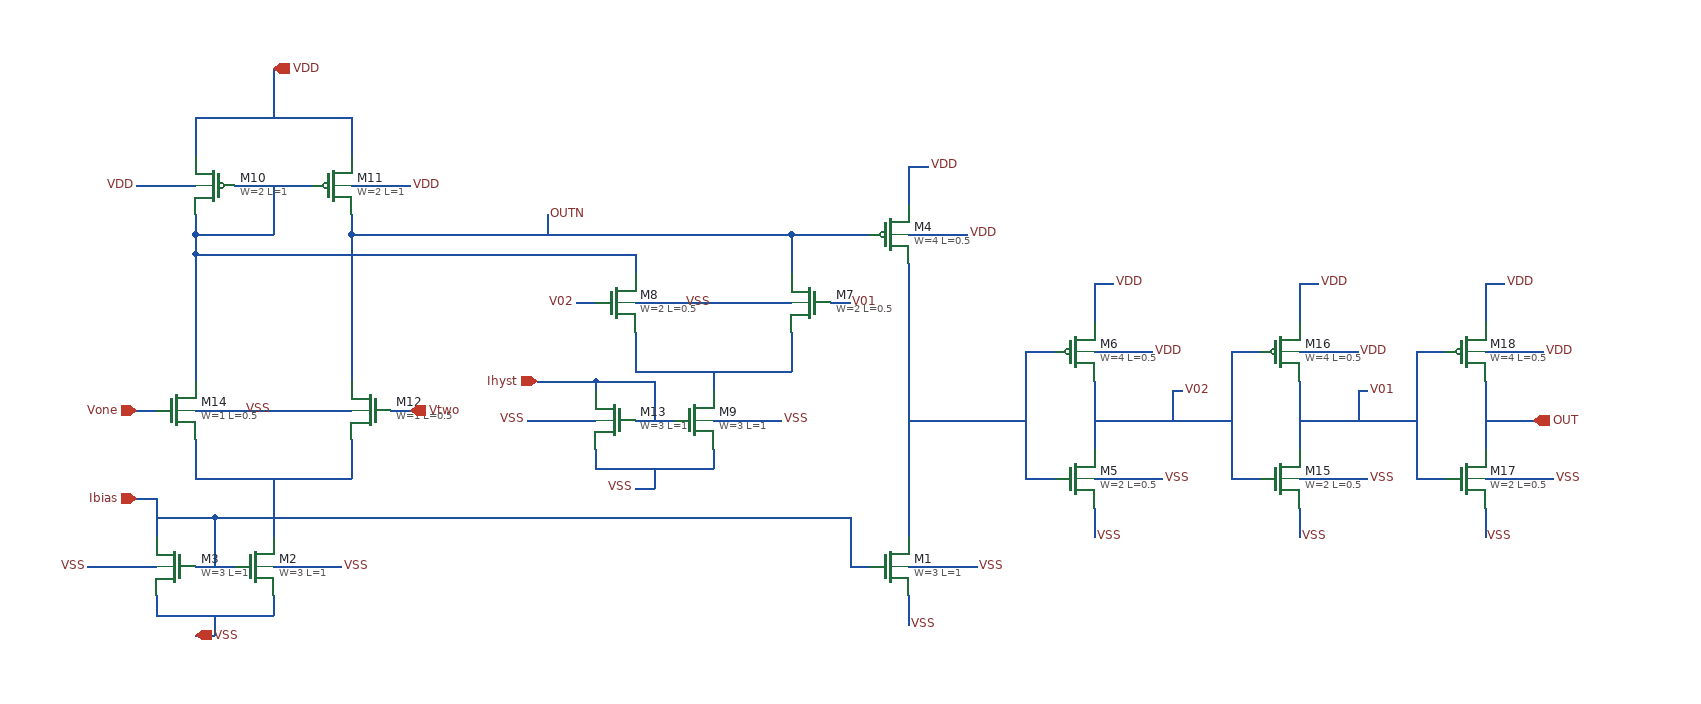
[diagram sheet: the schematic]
v {xschem version=3.1.0 file_version=1.2
}
G {}
K {}
V {}
S {}
E {}
N 120 -510 120 -470 {
lab=VDD}
N 40 -460 40 -420 {
lab=VDD}
N 200 -460 200 -420 {
lab=VDD}
N 80 -390 160 -390 {
lab=#net1}
N 200 -390 260 -390 {
lab=VDD}
N -20 -390 40 -390 {
lab=VDD}
N 40 -210 40 -190 {
lab=#net1}
N 200 -210 200 -190 {
lab=OUTN}
N 40 -360 40 -340 {
lab=#net1}
N -20 -160 0 -160 {
lab=Vone}
N 240 -160 260 -160 {
lab=Vtwo}
N 40 -160 200 -160 {
lab=VSS}
N 40 -460 200 -460 {
lab=VDD}
N 120 -470 120 -460 {
lab=VDD}
N 200 -130 200 -90 {
lab=#net2}
N 40 -90 200 -90 {
lab=#net2}
N 40 -130 40 -90 {
lab=#net2}
N 120 -90 120 -70 {
lab=#net2}
N 60 50 60 70 {
lab=VSS}
N 40 70 60 70 {
lab=VSS}
N 770 -340 830 -340 {
lab=VDD}
N 770 -410 790 -410 {
lab=VDD}
N 770 -410 770 -370 {
lab=VDD}
N 770 -310 770 -240 {
lab=#net3}
N 770 30 770 50 {
lab=VSS}
N 770 50 770 60 {
lab=VSS}
N 120 -390 120 -340 {
lab=#net1}
N 0 30 0 50 {
lab=VSS}
N 0 50 120 50 {
lab=VSS}
N 120 30 120 50 {
lab=VSS}
N 40 0 80 0 {
lab=Ibias}
N 120 -70 120 -30 {
lab=#net2}
N -20 -70 0 -70 {
lab=Ibias}
N 0 -70 0 -30 {
lab=Ibias}
N 60 -50 60 0 {
lab=Ibias}
N 0 -50 60 -50 {
lab=Ibias}
N 120 0 190 0 {
lab=VSS}
N -70 0 0 0 {
lab=VSS}
N 770 0 840 0 {
lab=VSS}
N 770 0 840 0 {
lab=VSS}
N 960 -220 1020 -220 {
lab=VDD}
N 960 -290 980 -290 {
lab=VDD}
N 960 -290 960 -250 {
lab=VDD}
N 960 -190 960 -120 {
lab=V02}
N 960 -60 960 -40 {
lab=VSS}
N 960 -40 960 -30 {
lab=VSS}
N 890 -90 920 -90 {
lab=#net3}
N 890 -220 890 -90 {
lab=#net3}
N 890 -220 920 -220 {
lab=#net3}
N 960 -150 1010 -150 {
lab=V02}
N 960 -90 1030 -90 {
lab=VSS}
N 960 -90 1030 -90 {
lab=VSS}
N 490 -320 490 -300 {
lab=#net1}
N 650 -320 650 -300 {
lab=OUTN}
N 430 -270 450 -270 {
lab=V02}
N 690 -270 710 -270 {
lab=V01}
N 490 -270 650 -270 {
lab=VSS}
N 650 -240 650 -200 {
lab=#net4}
N 490 -200 650 -200 {
lab=#net4}
N 490 -240 490 -200 {
lab=#net4}
N 510 -100 510 -80 {
lab=VSS}
N 490 -80 510 -80 {
lab=VSS}
N 450 -120 450 -100 {
lab=VSS}
N 450 -100 570 -100 {
lab=VSS}
N 570 -120 570 -100 {
lab=VSS}
N 490 -150 530 -150 {
lab=Ihyst}
N 570 -150 640 -150 {
lab=VSS}
N 380 -150 450 -150 {
lab=VSS}
N 390 -190 450 -190 {
lab=Ihyst}
N 450 -190 450 -180 {
lab=Ihyst}
N 450 -190 510 -190 {
lab=Ihyst}
N 510 -190 510 -150 {
lab=Ihyst}
N 570 -200 570 -180 {
lab=#net4}
N 200 -360 200 -340 {
lab=OUTN}
N 40 -340 40 -320 {
lab=#net1}
N 40 -340 120 -340 {
lab=#net1}
N 40 -320 490 -320 {
lab=#net1}
N 650 -340 650 -320 {
lab=OUTN}
N 200 -340 650 -340 {
lab=OUTN}
N 650 -340 730 -340 {
lab=OUTN}
N 70 -50 710 -50 {
lab=Ibias}
N 710 0 730 -0 {
lab=Ibias}
N 710 -50 710 0 {
lab=Ibias}
N 770 -240 770 -30 {
lab=#net3}
N 200 -340 200 -210 {
lab=OUTN}
N 40 -320 40 -210 {
lab=#net1}
N 60 -50 70 -50 {
lab=Ibias}
N 770 -150 890 -150 {
lab=#net3}
N 400 -360 400 -340 {
lab=OUTN}
N 1170 -220 1230 -220 {
lab=VDD}
N 1170 -290 1190 -290 {
lab=VDD}
N 1170 -290 1170 -250 {
lab=VDD}
N 1170 -190 1170 -120 {
lab=V01}
N 1170 -60 1170 -40 {
lab=VSS}
N 1170 -40 1170 -30 {
lab=VSS}
N 1100 -90 1130 -90 {
lab=V02}
N 1100 -220 1100 -90 {
lab=V02}
N 1100 -220 1130 -220 {
lab=V02}
N 1170 -150 1220 -150 {
lab=V01}
N 1170 -90 1240 -90 {
lab=VSS}
N 1170 -90 1240 -90 {
lab=VSS}
N 1010 -150 1100 -150 {
lab=V02}
N 1040 -180 1050 -180 {
lab=V02}
N 1040 -180 1040 -150 {
lab=V02}
N 1360 -220 1420 -220 {
lab=VDD}
N 1360 -290 1380 -290 {
lab=VDD}
N 1360 -290 1360 -250 {
lab=VDD}
N 1360 -190 1360 -120 {
lab=OUT}
N 1360 -60 1360 -40 {
lab=VSS}
N 1360 -40 1360 -30 {
lab=VSS}
N 1290 -90 1320 -90 {
lab=V01}
N 1290 -220 1290 -90 {
lab=V01}
N 1290 -220 1320 -220 {
lab=V01}
N 1360 -150 1410 -150 {
lab=OUT}
N 1360 -90 1430 -90 {
lab=#net5}
N 1360 -90 1430 -90 {
lab=#net5}
N 1220 -150 1290 -150 {
lab=V01}
N 1230 -180 1240 -180 {
lab=V01}
N 1230 -180 1230 -150 {
lab=V01}
C {devices/lab_pin.sym} 980 -290 0 1 {name=l13 sig_type=std_logic lab=VDD}
C {sky130_fd_pr/pfet_01v8_lvt.sym} 60 -390 0 1 {name=M10
L=1
W=2
nf=2
mult=1
ad="'int((nf+1)/2) * W/nf * 0.29'" 
pd="'2*int((nf+1)/2) * (W/nf + 0.29)'"
as="'int((nf+2)/2) * W/nf * 0.29'" 
ps="'2*int((nf+2)/2) * (W/nf + 0.29)'"
nrd="'0.29 / W'" nrs="'0.29 / W'"
sa=0 sb=0 sd=0
model=pfet_01v8_lvt
spiceprefix=X
}
C {sky130_fd_pr/pfet_01v8_lvt.sym} 180 -390 0 0 {name=M11
L=1
W=2
nf=2
mult=1
ad="'int((nf+1)/2) * W/nf * 0.29'" 
pd="'2*int((nf+1)/2) * (W/nf + 0.29)'"
as="'int((nf+2)/2) * W/nf * 0.29'" 
ps="'2*int((nf+2)/2) * (W/nf + 0.29)'"
nrd="'0.29 / W'" nrs="'0.29 / W'"
sa=0 sb=0 sd=0
model=pfet_01v8_lvt
spiceprefix=X
}
C {devices/lab_pin.sym} -20 -390 0 0 {name=l16 sig_type=std_logic lab=VDD}
C {devices/lab_pin.sym} 260 -390 2 0 {name=l17 sig_type=std_logic lab=VDD}
C {sky130_fd_pr/nfet_01v8_lvt.sym} 220 -160 0 1 {name=M12
L=0.5
W=1
nf=1
mult=1
model=nfet_01v8_lvt
spiceprefix=X}
C {sky130_fd_pr/nfet_01v8_lvt.sym} 20 -160 0 0 {name=M14
L=0.5
W=1
nf=1
mult=1
model=nfet_01v8_lvt
spiceprefix=X}
C {devices/lab_pin.sym} 120 -160 1 1 {name=l18 sig_type=std_logic lab=VSS}
C {devices/lab_pin.sym} 960 -30 0 1 {name=l22 sig_type=std_logic lab=VSS}
C {devices/ipin.sym} -20 -160 0 0 {name=p6 lab=Vone}
C {devices/ipin.sym} 260 -160 0 1 {name=p7 lab=Vtwo}
C {devices/lab_pin.sym} 400 -360 0 1 {name=l24 sig_type=std_logic lab=OUTN}
C {sky130_fd_pr/nfet_01v8_lvt.sym} 750 0 0 0 {name=M1
L=1
W=3
nf=1
mult=1
model=nfet_01v8_lvt
spiceprefix=X}
C {devices/lab_pin.sym} 770 60 0 1 {name=l1 sig_type=std_logic lab=VSS}
C {devices/lab_pin.sym} 830 -340 2 0 {name=l4 sig_type=std_logic lab=VDD}
C {sky130_fd_pr/pfet_01v8_lvt.sym} 750 -340 0 0 {name=M4
L=0.5
W=4
nf=1
mult=1
ad="'int((nf+1)/2) * W/nf * 0.29'" 
pd="'2*int((nf+1)/2) * (W/nf + 0.29)'"
as="'int((nf+2)/2) * W/nf * 0.29'" 
ps="'2*int((nf+2)/2) * (W/nf + 0.29)'"
nrd="'0.29 / W'" nrs="'0.29 / W'"
sa=0 sb=0 sd=0
model=pfet_01v8_lvt
spiceprefix=X
}
C {sky130_fd_pr/nfet_01v8_lvt.sym} 100 0 0 0 {name=M2
L=1
W=3
nf=1
mult=1
model=nfet_01v8_lvt
spiceprefix=X}
C {sky130_fd_pr/nfet_01v8_lvt.sym} 20 0 0 1 {name=M3
L=1
W=3
nf=1
mult=1
model=nfet_01v8_lvt
spiceprefix=X}
C {devices/iopin.sym} -20 -70 2 0 {name=p4 lab=Ibias}
C {devices/lab_pin.sym} 190 0 0 1 {name=l2 sig_type=std_logic lab=VSS}
C {devices/lab_pin.sym} -70 0 0 0 {name=l3 sig_type=std_logic lab=VSS}
C {devices/iopin.sym} 40 70 0 1 {name=p5 lab=VSS}
C {sky130_fd_pr/nfet_01v8_lvt.sym} 940 -90 0 0 {name=M5
L=0.5
W=2
nf=1
mult=1
model=nfet_01v8_lvt
spiceprefix=X}
C {devices/lab_pin.sym} 1020 -220 2 0 {name=l8 sig_type=std_logic lab=VDD}
C {sky130_fd_pr/pfet_01v8_lvt.sym} 940 -220 0 0 {name=M6
L=0.5
W=4
nf=1
mult=1
ad="'int((nf+1)/2) * W/nf * 0.29'" 
pd="'2*int((nf+1)/2) * (W/nf + 0.29)'"
as="'int((nf+2)/2) * W/nf * 0.29'" 
ps="'2*int((nf+2)/2) * (W/nf + 0.29)'"
nrd="'0.29 / W'" nrs="'0.29 / W'"
sa=0 sb=0 sd=0
model=pfet_01v8_lvt
spiceprefix=X
}
C {devices/iopin.sym} 120 -510 0 1 {name=p8 lab=VDD
}
C {devices/lab_pin.sym} 1030 -90 0 1 {name=l10 sig_type=std_logic lab=VSS}
C {devices/lab_pin.sym} 790 -410 2 0 {name=l11 sig_type=std_logic lab=VDD}
C {devices/lab_pin.sym} 840 0 0 1 {name=l5 sig_type=std_logic lab=VSS}
C {sky130_fd_pr/nfet_01v8_lvt.sym} 670 -270 0 1 {name=M7
L=0.5
W=2
nf=1
mult=1
model=nfet_01v8_lvt
spiceprefix=X}
C {sky130_fd_pr/nfet_01v8_lvt.sym} 470 -270 0 0 {name=M8
L=0.5
W=2
nf=1
mult=1
model=nfet_01v8_lvt
spiceprefix=X}
C {devices/lab_pin.sym} 570 -270 1 1 {name=l6 sig_type=std_logic lab=VSS}
C {sky130_fd_pr/nfet_01v8_lvt.sym} 550 -150 0 0 {name=M9
L=1
W=3
nf=1
mult=1
model=nfet_01v8_lvt
spiceprefix=X}
C {sky130_fd_pr/nfet_01v8_lvt.sym} 470 -150 0 1 {name=M13
L=1
W=3
nf=1
mult=1
model=nfet_01v8_lvt
spiceprefix=X}
C {devices/iopin.sym} 390 -190 2 0 {name=p3 lab=Ihyst}
C {devices/lab_pin.sym} 640 -150 0 1 {name=l12 sig_type=std_logic lab=VSS}
C {devices/lab_pin.sym} 380 -150 0 0 {name=l14 sig_type=std_logic lab=VSS}
C {devices/lab_pin.sym} 490 -80 2 1 {name=l15 sig_type=std_logic lab=VSS}
C {devices/lab_pin.sym} 1190 -290 0 1 {name=l21 sig_type=std_logic lab=VDD}
C {devices/lab_pin.sym} 1170 -30 0 1 {name=l23 sig_type=std_logic lab=VSS}
C {sky130_fd_pr/nfet_01v8_lvt.sym} 1150 -90 0 0 {name=M15
L=0.5
W=2
nf=1
mult=1
model=nfet_01v8_lvt
spiceprefix=X}
C {devices/lab_pin.sym} 1230 -220 2 0 {name=l26 sig_type=std_logic lab=VDD}
C {sky130_fd_pr/pfet_01v8_lvt.sym} 1150 -220 0 0 {name=M16
L=0.5
W=4
nf=1
mult=1
ad="'int((nf+1)/2) * W/nf * 0.29'" 
pd="'2*int((nf+1)/2) * (W/nf + 0.29)'"
as="'int((nf+2)/2) * W/nf * 0.29'" 
ps="'2*int((nf+2)/2) * (W/nf + 0.29)'"
nrd="'0.29 / W'" nrs="'0.29 / W'"
sa=0 sb=0 sd=0
model=pfet_01v8_lvt
spiceprefix=X
}
C {devices/lab_pin.sym} 1240 -90 0 1 {name=l28 sig_type=std_logic lab=VSS}
C {devices/lab_pin.sym} 1050 -180 0 1 {name=l29 sig_type=std_logic lab=V02}
C {devices/lab_pin.sym} 430 -270 2 1 {name=l20 sig_type=std_logic lab=V02}
C {devices/lab_pin.sym} 1380 -290 0 1 {name=l30 sig_type=std_logic lab=VDD}
C {devices/lab_pin.sym} 1360 -30 0 1 {name=l31 sig_type=std_logic lab=VSS}
C {sky130_fd_pr/nfet_01v8_lvt.sym} 1340 -90 0 0 {name=M17
L=0.5
W=2
nf=1
mult=1
model=nfet_01v8_lvt
spiceprefix=X}
C {devices/lab_pin.sym} 1420 -220 2 0 {name=l33 sig_type=std_logic lab=VDD}
C {sky130_fd_pr/pfet_01v8_lvt.sym} 1340 -220 0 0 {name=M18
L=0.5
W=4
nf=1
mult=1
ad="'int((nf+1)/2) * W/nf * 0.29'" 
pd="'2*int((nf+1)/2) * (W/nf + 0.29)'"
as="'int((nf+2)/2) * W/nf * 0.29'" 
ps="'2*int((nf+2)/2) * (W/nf + 0.29)'"
nrd="'0.29 / W'" nrs="'0.29 / W'"
sa=0 sb=0 sd=0
model=pfet_01v8_lvt
spiceprefix=X
}
C {devices/opin.sym} 1410 -150 0 0 {name=p2 lab=OUT}
C {devices/lab_pin.sym} 1430 -90 0 1 {name=l35 sig_type=std_logic lab=VSS}
C {devices/lab_pin.sym} 1240 -180 0 1 {name=l36 sig_type=std_logic lab=V01}
C {devices/lab_pin.sym} 710 -270 0 1 {name=l19 sig_type=std_logic lab=V01}
